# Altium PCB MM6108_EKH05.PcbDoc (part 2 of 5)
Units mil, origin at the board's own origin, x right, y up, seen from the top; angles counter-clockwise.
Board outline 6023.62 x 3425.2 mil, 4 copper layers (Top Layer, Ground Plane, Middle Layer, Bottom Layer), stack 76.15 mil thick; 212 components, 163 nets, 749 pads, 1477 vias.

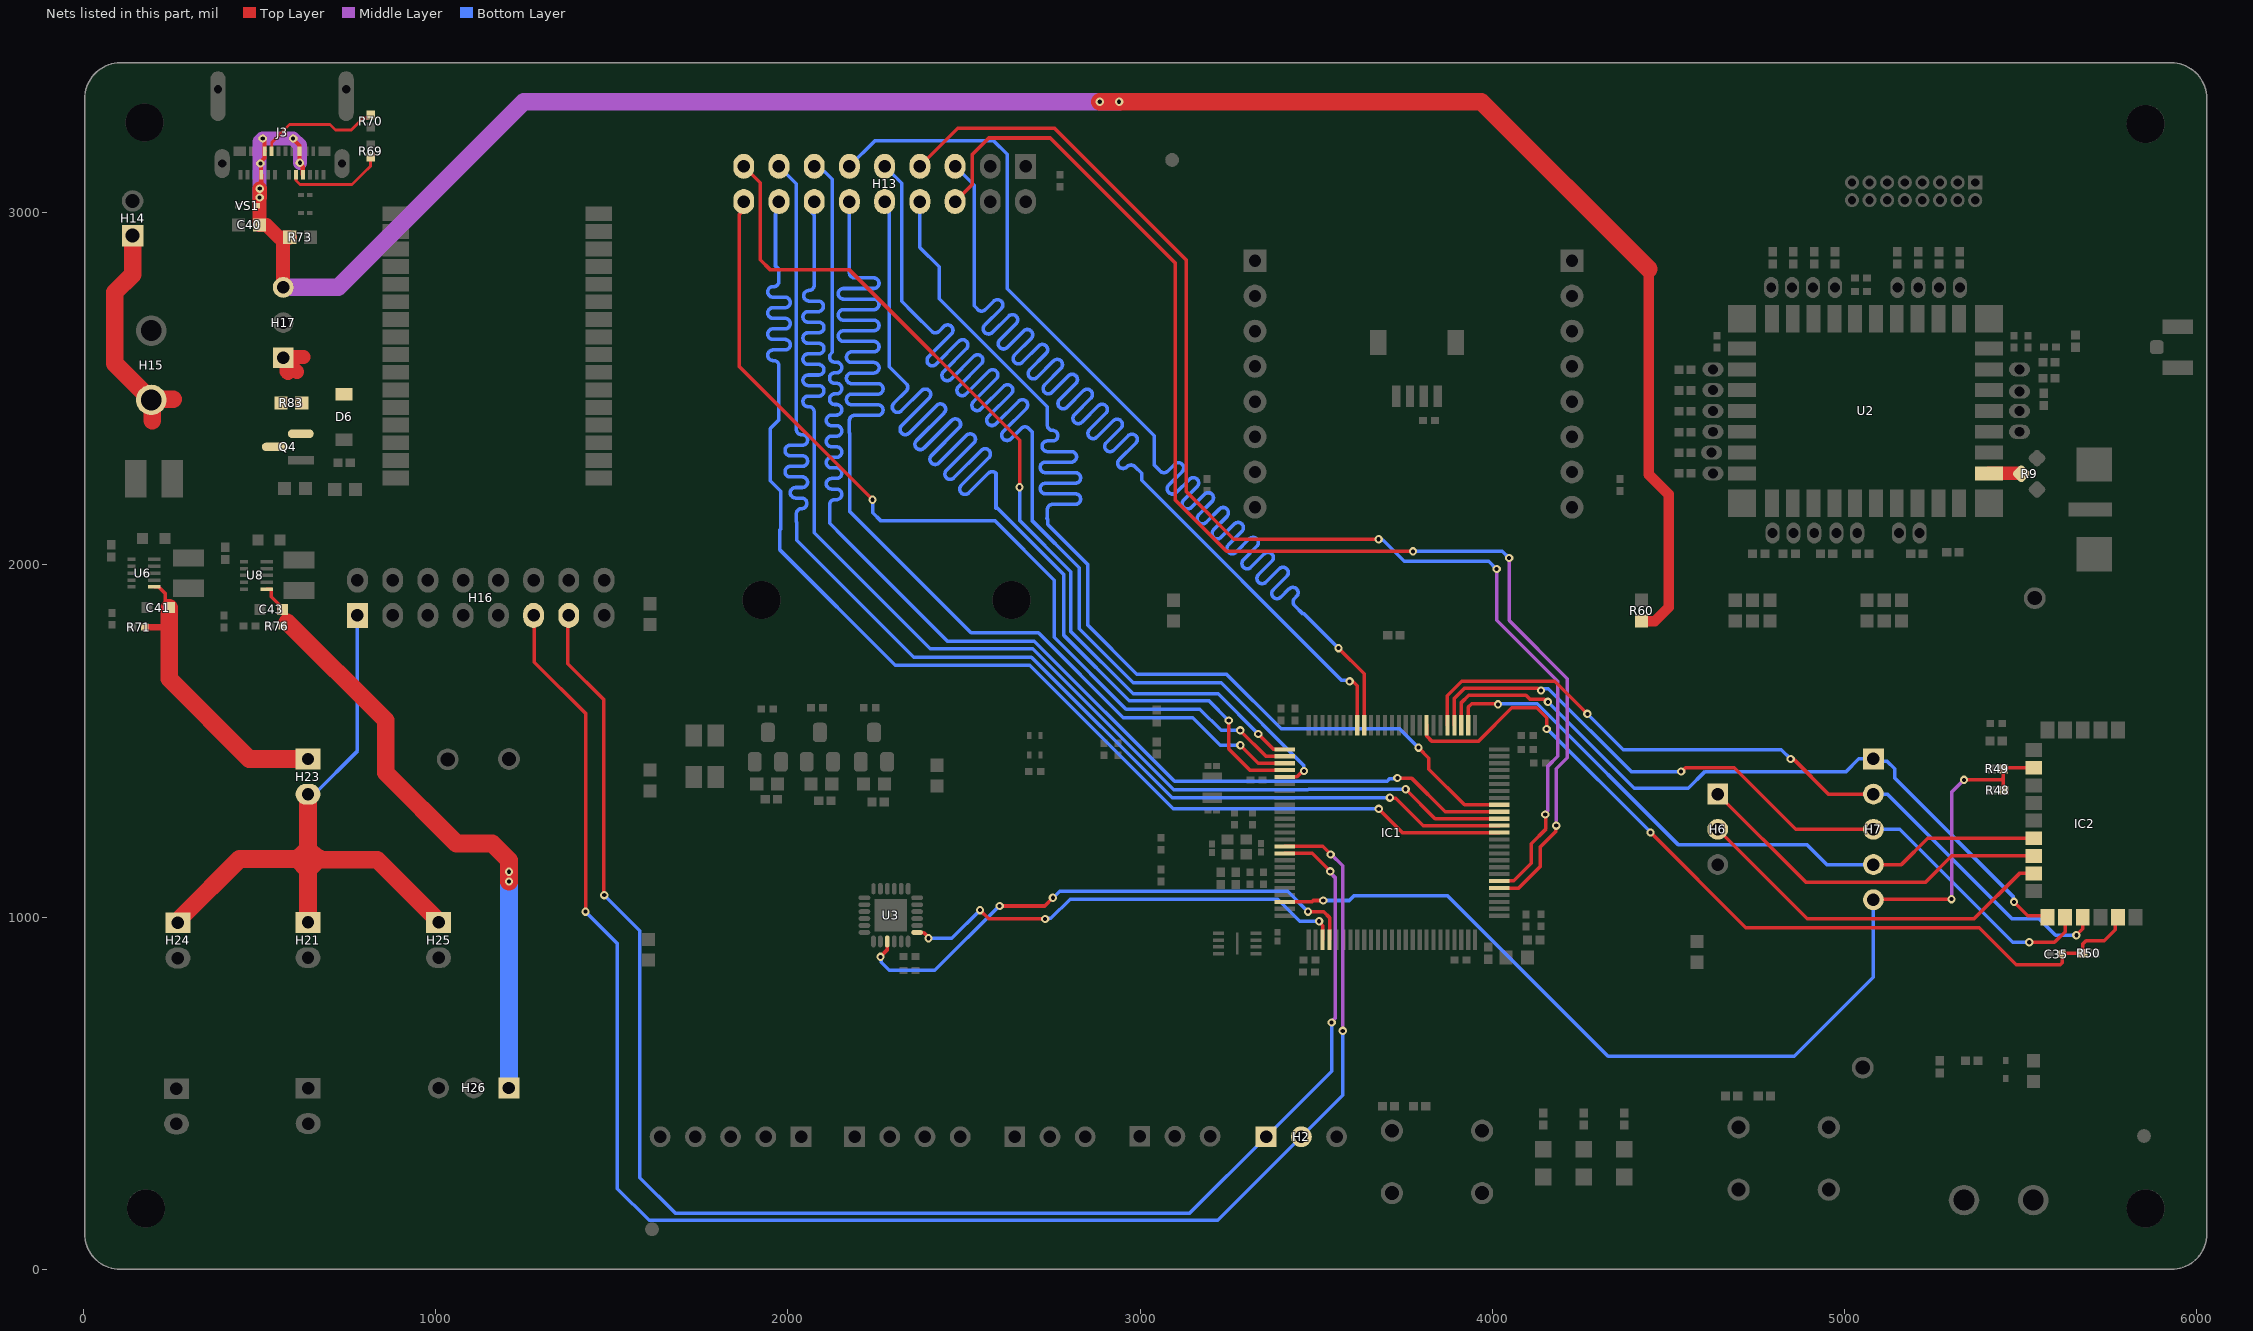
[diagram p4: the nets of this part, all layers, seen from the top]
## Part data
C1: library part CAP0157-11, "CAP CER 4.7UF 10V ±20% X5R 0402", Component Rating=X5R, Package=0402, Tolerance=20%, Voltage=10V
C2 C4 C6 C8 C11 C15 C16 C18 C28 C29 C31 C34 C37 C39 C45 C46 C47 C48: library part CAP0068-11, "CAP CER 100NF 50V ±10% X7R 0402", Component Rating=X7R, Package=0402, Tolerance=10%, Voltage=50V
C3 C5 C7 C9 C10 C14 C27 C30 C38: library part CAP0046-13, "CAP CER 10UF 10V 20% X5R 0402", Package=0402, Tolerance=20%, Voltage=10V
C12 C13 C32 C33: library part CAP0055-10, "CAP CER 2.2UF 25V ±20% X5R 0402", Component Rating=X5R, Package=0402, Tolerance=20%, Voltage=25V
C17 C21: library part CAP0168-10, "CAP CER 1UF 25V ±10% X5R 0402", Component Rating=X5R, Package=0402, Tolerance=10%, Voltage=25V
C19 C20: library part CAP0196-10, "CAP CER 100NF 10V ±10% X5R 0402", Component Rating=X5R, Package=0402, Tolerance=10%
C22 C23: library part CAP0010-6, "CAP CER 12PF 25V ±5% C0G/NP0 0201", Component Rating="C0G, NPO", Package=0201, Tolerance=5%, Voltage=25V
C24: library part CAP0134-6, "CAP CER 100NF 6.3V ±10% X5R 0201", Component Rating=X5R, Package=0201, Tolerance=10%
C25 C26: library part CAP0010-6, "CAP CER 12PF 25V ±5% C0G/NP0 0201", Component Rating="C0G, NPO", Package=0201, Tolerance=5%
C35: library part CAP0023-11, "CAP CER 10NF 25V ±10% X7R 0402", Component Rating=X7R, Package=0402, Tolerance=10%, Voltage=25V
C36: library part CAP0023-10, "CAP CER 10NF 25V ±10% X7R 0402", Component Rating=X7R, Package=0402, Tolerance=10%, Voltage=25V
C40: library part CAP0197-5, "CAP CER 10UF 25V ±20% X5R 0603", Component Rating=X5R, Package=0603, Tolerance=20%, Voltage=25V
C41 C43: library part CAP0243-1, "Multilayer Ceramic Capacitor, 22 uF, 6.3 V, ± 20%, X5R, 0603 [1608 Metric]", Case Code (Imperial)=0603, Case Code (Metric)=1608, Dielectric=X5R, Max Operating Temperature=85°C, Min Operating Temperature=-55°C, Package Quantity=1, Tolerance=20%, Voltage Rating=6.3V
C42 C44: library part CAP0244-1, "Multilayer Ceramic Capacitor, 10 uF, 6.3 V, ± 20%, X5R, 0603 [1608 Metric]", Case Code (Imperial)=0603, Case Code (Metric)=1608, Max Operating Temperature=85°C, Min Operating Temperature=-55°C, Package Quantity=1, Tolerance=20%, Voltage Rating=6.3V
C49: library part CAP0047-3, "CAP CER 100UF 10V ±20% X5R 1210", Component Rating=X5R, Package=1210, Tolerance=20%, Voltage=10V
D1: library part DIO0016-2, "LED, Red Clear,2.0V, SMD, 0805, RoHS", Component Rating="Clear, 2.0V", Package=SMD-0805
D2: library part DIO0015-2, "LED, Green Clear,2.0V, SMD, 0805, RoHS", Component Rating="Clear, 2.0V", Package=SMD-0805
D3: library part DIO0018-2, "LED, Blue Clear,3.3V, SMD, 0805, RoHS", Component Rating="Clear, 3.3V", Package=SMD-0805
D4: library part DIO0071-3, "TVS DIODE 3.3VWM 11.2VC SOD523", Package=SOD-123, Voltage=3.3V
D5: library part DIO0045-2, "LED, RGB, 624nm Red, 525nm Green, 470nm Blue LED Indication - Discrete 2V Red, 3.3V Green, 3.3V Blue 1206 (3216 Metric)", Component Rating="Clear, 3.3V", Current=20mA, Package="LED, 1206", Voltage=3.3V
D6: library part DIO0072-1, "DIODE ZENER 5.1V 500MW SOD-123"
D11 D12: library part DIO0043-4, "TVS DIODE 3VWM ST020", Package=0201, Power=20W, Voltage=3V
FID1 FID2 FID3: library part PAD0002-2, "1mm Round Fiducial, 0.5mm Space"
H1 H7: library part HDR0119-2, "2011 Series Single Row 5 Position 2.54 mm 3 A Straight Gold Flash Pin Header"
H2 H6 H8 H10 H17 H26: library part HDR0008-2, "Conn Straight Header 3x1 0.100\" 3 POS", Package=THRU-Hole
H4: library part JCK0091-1, "U.FL RF Connector", Package=SMT
H5: library part JCK0086-2, "CONN,Vertical FTSH Series,0.05\"16 Pins, Through Hole", Package="FTSH 108D"
H9: library part HDR0114-1, "Board Connector, 4 Contact(s), 1 Row(s), Male, Straight, Solder Terminal, 1x4"
H11 H15: library part JCK0020-1, "CONN TERM BLOCK 5MM 2POS", Package=THRU-Hole
H12: library part HDR0118-1, "QWIIC Connector, JST"
H13: library part HDR0112-1, "Board Connector, 18 Contact(s), 2 Row(s), Female, Straight, 0.1 inch Pitch, Solder Terminal, Locking"
H14: library part HDR0117-1, "Board Connector, 2 Contact(s), 1 Row(s), Male, Straight, Solder Terminal,"
H16: library part HDR0116-2
H19 H21 H22 H23 H24 H25: library part HDR0006-2, "Conn Straight Header 2x1 0.100\" 2 POS", Package=THRU-Hole
IC1: library part ICT0224-2, Package=LQFP-100
IC2: library part ICT0219-4, "BLUENRGM2SP"
J1 J2: library part HDR0120-3, "CONN RCPT 8POS 0.1 GOLD PCB"
J3: library part JCK0027-1, "CONN RCP USB3.1 TYPEC 24P SMD RA"
J5 J8 J9 J10 J11 J12 J13 J14 J15 J16 J17 J18 J19 J20 J21: library part CMP-00006-6, "Shunts/Jumper Connector", Manufacturer Series=QPC, Rated Current (Signal)=3A
J22: library part JCK0138-4, "Wanshih RF SMD SMA connector with 2 GND pillars - Smaller Connector Barrel"
L1: library part IND0038-5, "INDUCTOR 2.2UH 10% 0603 SMD", Current=300mA, DC Resistance=300mOhm, Frequency=80MHz, Package=0603, Tolerance=20%
L2: library part IND0062-6, "BEAD 60OHMS 2500MA 32 MOHM", Current=2.5A, DC Resistance=32mOhm, Package=0402
L3 L4: library part IND0139-3, Current=4, DC Resistance=27mOhm, Package=1008
M1 M2 M3 M4: library part PAD0031, "MH NPTH 3.00mm DIA 2.75mm HOLE"
MH1 MH2: library part PAD0009-2, "MH NPTH 3.00mm DIA 2.75mm HOLE"
Q1 Q2 Q3: library part TSR0015-4, "MOSFET N-CH 60V 190MA TO236AB", Current=190mA, Package=SOT-23-3, Power=265mW, Voltage=60V
Q4: library part TSR0020-1, "Small Signal Field-Effect Transistor", Avalanche Energy Rating (Eas)=33mJ, Drain Current-Max (Abs) (ID)=4.3A, Drain-source On Resistance-Max=50mR, DS Breakdown Voltage-Min=12V, Max Operating Temperature=150°C, Operating Mode="ENHANCEMENT MODE", Package Body Material=Plastic, Package Shape=Rectangular, Package Style="SMALL OUTLINEMeter", Peak Reflow Temperature (Cel)=260°C, Power Dissipation-Max (Abs)=1.3W, Pulsed Drain Current-Max (IDM)=34A, Time @ Peak Reflow Temperature-Max (s)=30s
R1 R2 R7 R8 R51: library part RES0043-8, "RES SMD 10K OHM ±1% 1/16W 0402", Package=0402, Power=1/16W, Tolerance=1%
R3 R4 R5 R6: library part RES0004-8, "RES SMD 1K OHM ±1% 1/10W 0402", Package=0402, Power=1/10W, Tolerance=1%
R9: library part RES0280, "Ohms Jumper Chip Resistor 0603 ( 1608 Metric) - RES_AC", Manufacturer 1=Rohm, Manufacturer 2=Yageo, Manufacturer Part Number 1=MCR03EZPJ000, Manufacturer Part Number 2=RC0603JR-070RL, Package=0603, Power=1/10W, Supplier Part Number 1=311-0.0GRCT-ND, Tolerance=5%
R10 R12 R31 R32 R33 R41 R42 R43 R47 R53 R54 R55 R56 R60 R61 R62 R63 R64 R73 R83: library part RES0119-6, "RES SMD 0R OHM ±5% 1/10W 0603", Package=0603, Power=1/10W, Tolerance=5%
R11 R14 R15 R16 R17 R18 R19 R20 R27 R28 R29 R30 R34 R37 R39 R40 R65 R66 R67: library part RES0002-8, "RES SMD 10K OHM ±1% 1/10W 0402", Package=0402, Power=1/10W, Tolerance=1%
R21 R22 R23 R24 R25 R26 R50: library part RES0086-8, "RES SMD 47K OHM ±1% 1/16W 0402", Package=0402, Power=1/16W, Tolerance=1%
R35: library part RES0023-9, "RES SMD 100K OHM ±1% 1/16W 0402", Package=0402, Power=1/16W, Tolerance=1%
R36: library part RES0252-6, "RES SMD 150K OHM 1% 1/10W 0402", Package=0402, Power=1/10W, Tolerance=1%
R46: library part RES0064-8, "RES SMD 220K OHM ±1% 1/16W 0402", Package=0402, Power=1/16W, Tolerance=1%
R48 R49: library part RES0244-8, "RES SMD 10K OHM ±0.1% 1/16W 0402", Package=0402, Power=1/16W, Tolerance=0.1%
R52: library part RES0104-6, "RES SMD 100R OHM ±0 .1% 1/16W 0603", Package=0603, Power=1/16W, Tolerance="0 .1%"
R57: library part RES0025-9, "RES SMD 330R OHM ±1% 1/16W 0402", Package=0402, Power=1/16W, Tolerance=1%
R58: library part RES0042-9, "RES SMD 1K OHM ±1% 1/16W 0402", Package=0402, Power=1/16W, Tolerance=1%
R59: library part RES0061-9, "RES SMD 220R OHM ±1% 1/16W 0402", Package=0402, Power=1/16W, Tolerance=1%
R68 R74: library part RES0044-8, "RES SMD 100K OHM ±1% 1/16W 0402", Package=0402, Power=1/16W, Tolerance=1%
R69 R70: library part RES0094-8, "RES SMD 5K1 OHM ±1% 1/16W 0402", Package=0402, Power=1/16W, Tolerance=1%
R71 R76: library part RES0254-2, "RES 511K OHM 1% 1/16W 0402", Manufacturer 1=YAGEO, Manufacturer Part Number 1=RC0402FR-07511KL, Package=0402, Power=1/16W, Tolerance=1%
R72 R77: library part RES0255-2, "RES 91K OHM 1% 1/16W 0402", Manufacturer 1=YAGEO, Manufacturer Part Number 1=RC0402FR-0791KL, Package=0402, Power=1/16W, Tolerance=1%
R75: library part RES0025-8, "RES SMD 330R OHM ±1% 1/16W 0402", Package=0402, Power=1/16W, Tolerance=1%
R82 R85: library part RES0002-9, "RES SMD 10K OHM ±1% 1/10W 0402", Package=0402, Power=1/10W, Tolerance=1%
R84: library part RES0057-9, "RES SMD 180K OHM ±1% 1/16W 0402", Package=0402, Power=1/16W, Tolerance=1%
S1 S2: library part SWH0038-1, "Keypad Switch, 1 Switches, SPST, Momentary-tactile, 0.05A, 24VDC, 2.06N, 4 PCB Hole Cnt, Solder Terminal, Through Hole-straight", Contact Current(DC)-Max=50mA, Contact DC Max Rating R Load=.05A@24VDC, Contact Voltage(DC)-Max=24V, Max Operating Temperature=85°C, Min Operating Temperature=-35°C, Operating Force-Max=2.06N
TP1 TP2 TP3 TP4: library part TPN0006-3, "Test Point PCB, Black 0.040\"D"
U1: library part ICT0220-1, Package=USON8
U2: library part MOD0010-3, "MM61xx-MF08"
U3: library part ICT0109-3, "IC, Accelerometers High-performance ultra-low-power 3-axis accelerometer digital output for industr", Component Rating=3-Axis, Package=QFN-24
U4: library part ICT0108-3, "IC, Humidity Temperature Sensor 0 ~ 100% RH I²C ±1.8% RH 6 s Surface Mount", Package=DFN-4
U5: library part MOD0006-3, "MIKROBUS Module"
U6 U8: library part ICT0222-5, Package=10-VFDFN
U7: library part MOD0018-3
VS1: library part DIO0073-1, "TVS Diode,5V@9.4Amp, SOD-523 SMD", Current=9.4A, Package=SOD-523, Voltage=5V
X1: library part OSC0002-3, "OSC XTAL 30MHZ 10PF 10PPM SMD2016", Component Rating=10pF, Package=2016, Tolerance=10ppm
X2: library part OSC0044-1, "Parallel - Fundamental Quartz Crystal, 0.032768MHz Nom", Frequency Stability=0.025%, Frequency Tolerance=20ppm, Load Capacitance=4pF, Max Operating Temperature=85°C, Min Operating Temperature=-40°C, Operating Frequency-Nom=0.032768

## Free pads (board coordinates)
  oval 60x40 hole 28: 31(4622.05,2318.9) 31(4625.98,2259.84) 31(4625.98,2377.95) 31(4625.98,2437.01) 31(4625.98,2496.06) 31(4625.98,2555.12) 31(5496.06,2377.95) 31(5496.06,2437.01) 31(5496.06,2492.13) 31(5496.06,2555.12)
  oval 40x60 hole 28: 31(4791.34,2787.4) 31(4795.28,2090.55) 31(4850.39,2787.4) 31(4854.33,2090.55) 31(4909.45,2787.4) 31(4913.39,2090.55) 31(4972.44,2787.4) 31(4976.38,2090.55) 31(5035.43,2090.55) 31(5149.61,2787.4) 31(5153.54,2090.55) 31(5208.66,2787.4) 31(5212.6,2090.55) 31(5267.72,2787.4) 31(5326.77,2787.4)

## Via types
v1: diameter 23.62, hole 11.81, Top Layer to Bottom Layer, tented both sides, 1477 vias

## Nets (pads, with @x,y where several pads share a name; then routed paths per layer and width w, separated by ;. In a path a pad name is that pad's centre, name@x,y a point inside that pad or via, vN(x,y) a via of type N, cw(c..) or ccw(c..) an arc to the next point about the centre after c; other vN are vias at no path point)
3V3: C41.2 H23.1 R71.1 U6.6 | length 843.4
  Top Layer w10: U6.6@201.34,1937.32 213.98,1937.32 232.71,1918.59 232.71,1889.48 C41.2@243.46,1878.74
  Top Layer w18: R71.1@173.77,1823.15 243.46,1823.15
  Top Layer w50: C41.2@243.46,1878.74 243.46,1823.15 243.46,1676.54 471,1449 H23.1@637.35,1449
3V3_SYS: H16.1 H21.1 H23.2 H24.1 H25.1 | length 1939
  Top Layer w10: 637.35,1237 655.13,1237
  Top Layer w50: H24.1@277.13,999.32 442.81,1165 592.83,1165 ; 603.92,1166.98 637.1,1133.8 670.28,1166.98 ; 609.54,1166.98 637.1,1194.54 664.66,1166.98 ; H21.1@637.35,985 637.35,1157.08 637.35,1194.54 637.35,1237 H23.2@637.35,1349 ; 662.56,1163 833.89,1163 997.57,999.32 997.57,989.53 1002.09,985 H25.1@1008,985
  Bottom Layer w10: H23.2@637.35,1349 655,1349 777.76,1471.76 H16.1@777.76,1856.69
4V3: C43.2 H26.1 R76.1 U8.6 | length 1751.7
  Top Layer w10: U8.6@520.43,1930.63 533.07,1930.63 533.15,1930.55 533.15,1909.97 C43.2@567.15,1875.97
  Top Layer w50: 578.92,1837.7 858,1558.62 858,1410 1059,1209 1160,1209 1208,1161 v1(1208,1101)
  Bottom Layer w50: H26.1@1208,515.12 v1(1208,1129)
+5V: C40.1 H17.3 J3.A4 J3.A9 J3.B4 J3.B9 R60.2 R73.2 VS1.K | length 6368.3
  Top Layer w12: v1(500.4,3068.15) 500.4,3071.29 504.72,3075.61 J3.A9@504.72,3107.48 504.24,3107.97 504.24,3137.67 v1(502.16,3139.75) 502.16,3142.9 514.08,3154.81 514.08,3173.92 J3.B4@514.57,3174.41 514.08,3174.9 514.08,3201.96 508.9,3207.14 v1(508.9,3210.28) ; v1(595.15,3210.4) 595.15,3208.83 612.99,3190.99 J3.B9@612.99,3174.41 ; v1@613.53,3142.37 J3.B9@613.53,3173.87 ; v1(614.17,3141.73) 614.17,3138.59 622.35,3130.41 622.35,3107.97 J3.A4@622.83,3107.48
  Top Layer w30: R60.2@4423.23,1840.55 4460.82,1840.55 4500,1879.73 4500,2200 4443.35,2256.65 4443.35,2840.11
  Top Layer w40: C40.1@499.53,2965 C40.1@500.15,2965 ; v1(500.4,3068.15) 500.4,3043.22 v1(500.15,3042.97) C40.1@500.15,2965 ; H17.3@566.93,2787.87 R73.2@566.93,2930 ; R73.2@585.47,2930 R73.2@566.93,2930 ; C40.1@500.15,2965 520,2965 555,2930 R73.2@566.93,2930
  Top Layer w50: v1(2885,3315) v1(2940,3315) 3968.46,3315 4443.35,2840.11
  Middle Layer w40: v1(500.15,3042.97) 500.15,3068 500,3068.15 500,3201.39 v1(508.9,3210.28) 509.02,3210.4 v1(595.15,3210.4) 614.17,3191.38 v1(614.17,3141.73)
  Middle Layer w50: H17.3@566.93,2787.87 722.87,2787.87 1250,3315 v1(2940,3315)
ACC_INT1: IC1.28 U3.7 | length 1299.2
  Top Layer w10: U3.7@2366.61,956.57 2367.33,955.85 2385.98,955.85 2399,942.83 v1(2399,940) ; v1(2545,1020) 2570,995 v1(2730,995) ; v1(3507.87,988.19) 3507.87,985.88 3517.72,976.04 IC1.28@3517.72,935.51
  Bottom Layer w10: v1(2399,940) 2465,940 v1(2545,1020) ; v1(2730,995) 2731.46,996.46 2746.46,996.46 2800.93,1050.93 3390.02,1050.93 3452.76,988.19 v1(3507.87,988.19)
ACC_INT2: IC1.29 U3.3 | length 1537.3
  Top Layer w10: v1(2262.7,887.22) 2262.7,888.05 2281.24,906.59 2281.24,930.26 U3.3@2281.96,930.98 ; v1(2600.75,1031.65) 2728.5,1031.65 v1(2751.97,1055.12) ; v1(3476.38,1015.75) 3520.52,1015.75 3537.4,998.87 IC1.29@3537.4,935.51
  Bottom Layer w10: v1(2262.7,887.22) 2264.89,885.02 2264.89,871.49 2287.38,849 2417,849 2599.65,1031.65 v1(2600.75,1031.65) ; v1(2751.97,1055.12) 2752.83,1055.12 2771.02,1073.31 3418.82,1073.31 v1(3476.38,1015.75)
ANT: R9.A U2.38 | length 92.5
  Top Layer w39: U2.38@5409.45,2259.84 5499.74,2259.84 5501.09,2258.49 R9.A@5501.35,2258.49
BAT_POS: H14.1 H15.2 Q4.3 R83.1 | length 652.9
  Top Layer w50: H14.1@139.45,2934.88 139.45,2824.45 88.93,2773.93 88.93,2571.86 H15.2@192.6,2468.19 ; 195,2410 195,2465.79 H15.2@192.6,2468.19 ; 255,2470 194.41,2470 H15.2@192.6,2468.19
BAT_VIN: D6.K H17.1 Q4.2 R83.2 | length 123.6
  Top Layer w40: 580,2545 576.46,2548.54 576.46,2578.35 H17.1@566.93,2587.87 569.05,2590 625,2590 ; H17.1@594.9,2559.9 606.46,2548.35
BLE_RESET_N: C35.2 IC1.83 IC2.19 R50.2 | length 2464.2
  Top Layer w10: IC1.83@3812.99,1544.8 3813.9,1543.9 3813.9,1513.09 3826.98,1500 3960.63,1500 4055.12,1594.49 4125.98,1594.49 4154.51,1565.97 4154.51,1534.67 v1(4153.79,1533.95) ; v1(4448.82,1240.16) 4718.98,970 5382.26,970 5487.26,865 5611.45,865 5617.3,870.86 5617.3,897.64 R50.2@5675.59,897.64 5676.38,897.64 5676.38,924.41 5685.04,933.07 5736.29,933.07 5767.72,964.49 5767.72,992.13 IC2.19@5775.59,1000
  Bottom Layer w10: v1(4153.79,1533.95) 4155.79,1533.95 4448.82,1240.92 v1(4448.82,1240.16)
BLE_SPI_CS: H7.4 IC1.77 IC2.11 | length 1882.4
  Top Layer w10: IC1.77@3931.1,1544.8 3931.1,1596.46 3940.69,1606.05 4013.87,1606.05 v1(4015.75,1604.17) ; H7.4@5081.42,1149.29 5161.1,1149.29 5235.83,1224.02 IC2.11@5536.22,1224.02
  Bottom Layer w10: v1(4015.75,1604.17) 4017.62,1606.05 4126.95,1606.05 4526.84,1206.16 4892.27,1206.16 4949.13,1149.29 H7.4@5081.42,1149.29
BLE_SPI_IRQ: H7.5 IC1.23 IC2.7 R48.2 R49.1 | length 3016.4
  Top Layer w10: IC1.23@3409.92,1043.31 3487.79,1043.31 3491.72,1047.24 v1(3519.6,1047.24) ; H7.5@5081.42,1049.29 5083.31,1051.18 v1(5303.15,1051.18) ; v1(5338.58,1389.76) 5444.76,1389.76 5450.39,1395.39 ; R48.2@5450.39,1362.2 5450.39,1395.39 ; IC2.7@5536.22,1424.02 5453.73,1424.02 R49.1@5450.39,1420.68 5450.39,1395.39
  Middle Layer w10: v1(5303.15,1051.18) 5303.15,1354.33 v1(5338.58,1389.76)
  Bottom Layer w10: v1(3519.6,1047.24) 3593.72,1047.24 3607.86,1061.38 3871.69,1061.38 4328.07,605 4856.97,605 5081.42,829.45 H7.5@5081.42,1049.29
BLE_SPI_MISO: H7.3 IC1.79 IC2.16 | length 2186.9
  Top Layer w10: IC1.79@3891.73,1544.8 3891.73,1620.78 3920.56,1649.61 4128.05,1649.61 4134.11,1643.54 v1(4137.8,1643.54) ; v1(4535.43,1413.39) 4537.49,1413.39 4548.1,1424 4686.24,1424 4860.94,1249.29 H7.3@5081.42,1249.29 ; v1(5524.02,928.55) 5595.33,928.55 5625.59,958.82 IC2.16@5625.59,1000
  Bottom Layer w10: v1(4137.8,1643.54) 4141.48,1643.54 4146.28,1648.34 4158.75,1648.34 4393.7,1413.39 v1(4535.43,1413.39) ; H7.3@5081.42,1249.29 5156.19,1249.29 5476.93,928.55 v1(5524.02,928.55)
BLE_SPI_MOSI: H7.2 IC1.80 IC2.17 | length 2243.2
  Top Layer w10: IC1.80@3872.05,1544.8 3872.05,1628.55 3912.78,1669.29 4177.17,1669.29 v1(4269.32,1577.14) ; v1(4846.46,1448.82) 4849.06,1446.21 4856.69,1446.21 4856.95,1445.94 4857.2,1445.94 4953.86,1349.29 H7.2@5081.42,1349.29 ; v1(5657.48,948.82) 5675.59,966.93 IC2.17@5675.59,1000
  Bottom Layer w10: v1(4269.32,1577.14) 4371.46,1475 4820.28,1475 v1(4846.46,1448.82) ; H7.2@5081.42,1349.29 5082.29,1348.42 5121.58,1348.42 5473.94,996.06 5551.18,996.06 5598.43,948.82 v1(5657.48,948.82)
BLE_SPI_SCK: H7.1 IC1.78 IC2.15 | length 2089.9
  Top Layer w10: IC1.78@3911.42,1544.8 3911.87,1545.26 3911.87,1609.38 3932.41,1629.92 4095.08,1629.92 4105.87,1619.13 4145.66,1619.13 4153.58,1611.21 v1(4157.27,1611.21) ; v1(5480.31,1043.31) 5519.69,1003.94 5571.65,1003.94 IC2.15@5575.59,1000
  Bottom Layer w10: v1(4157.27,1611.21) 4402.34,1366.14 4556.14,1366.14 4603.39,1413.39 5003.94,1413.39 5039.84,1449.29 H7.1@5081.42,1449.29 5087.8,1442.91 5120.09,1442.91 5141.73,1421.26 5141.73,1394.94 5477.88,1058.79 5477.88,1045.74 v1(5480.31,1043.31)
BLE_SWCLK: H6.1 IC2.12 | length 1032.1
  Top Layer w10: H6.1@4639.37,1349.29 4890.24,1098.43 5228.35,1098.43 5303.94,1174.02 IC2.12@5536.22,1174.02
BLE_SWDIO: H6.2 IC2.13 | length 1055.6
  Top Layer w10: H6.2@4639.37,1249.29 4893.66,995 5367.05,995 5496.06,1124.02 IC2.13@5536.22,1124.02
CAM_PWDN: H13.18 IC1.2 | length 2596.5
  Top Layer w10: H13.18@1874.41,3031.5 1865.02,3022.11 1865.02,2998.02 1862.2,2995.2 1862.2,2562.99 v1(2240.16,2185.04) ; v1(3284.13,1530.33) 3284.13,1529.59 3357.03,1456.69 IC1.2@3409.92,1456.69
  Bottom Layer w10: v1(2240.16,2185.04) 2240.16,2148.42 2262.59,2125.98 2586.61,2125.98 2755.91,1956.69 2755.91,1794.31 2959.67,1590.55 3169.45,1590.55 3229.67,1530.33 v1(3284.13,1530.33)
CAM_RESET: H13.17 IC1.1 | length 2582.2
  Top Layer w10: H13.17@1874.41,3131.5 1921.26,3084.65 1921.26,2866.14 1948.82,2838.58 2173.23,2838.58 2657.48,2354.33 v1(2657.48,2220.47) ; v1(3335,1520) 3377.72,1477.28 3409.02,1477.28 IC1.1@3409.92,1476.38
  Bottom Layer w10: v1(2657.48,2220.47) 2657.48,2125.98 2803.15,1980.31 2803.15,1810.74 2980.03,1633.86 3221.14,1633.86 v1(3335,1520)
CAM_XCLK: H13.8 IC1.67 | length 3411.7
  Top Layer w10: v1(3789.8,1481.21) 3819.45,1451.57 3819.45,1420.07 3920.62,1318.9 IC1.67@4019.21,1318.9
  Bottom Layer w10: H13.8@2374.41,3031.5 2374.41,2901.18 2429.13,2846.46 2429.13,2755.91 2736.22,2448.82 2736.22,2429.13 2736.22,2396.87 ccw(c2751.22,2396.87) 2751.22,2381.87 cw(c2751.22,2366.87) 2751.22,2351.87 2736.22,2351.87 ccw(c2736.22,2336.87) 2736.22,2321.87 2804.16,2321.87 cw(c2804.16,2306.87) 2804.16,2291.87 2730.79,2291.87 ccw(c2730.79,2276.87) 2730.79,2261.87 2815.61,2261.87 cw(c2815.61,2246.87) 2815.61,2231.87 2730.79,2231.87 ccw(c2730.79,2216.87) 2730.79,2201.87 2815.61,2201.87 cw(c2815.61,2186.87) 2815.61,2171.87 2751.22,2171.87 ccw(c2751.22,2156.87) 2736.22,2156.87 2736.22,2133.86 2734.25,2131.89 2737.16,2128.99 2737.16,2123.16 2737.16,2114.77 2850.39,2001.53 2850.39,1829.61 2990,1690 3245,1690 3400,1535 3736.02,1535 v1(3789.8,1481.21)
CC1: J3.A5 R69.1 | length 279.7
  Top Layer w8: J3.A5@603.15,3107.48 603.54,3107.09 603.54,3091.46 615,3080 762.32,3080 806.01,3123.69 806.8,3123.69 815,3131.89 R69.1@815,3157.68
CC2: J3.B5 R70.1 | length 350.8
  Top Layer w8: J3.B5@534.25,3174.41 534.25,3199.25 585,3250 700,3250 715,3235 760,3235 793.33,3268.33 806.8,3268.33 815,3276.54 R70.1@815,3277.32
DBG_UART_STM_RX: H2.2 H16.11 IC1.15 | length 4807.8
  Top Layer w10: H16.11@1280,1855.9 1280,1723.94 1425.2,1578.74 v1(1425.2,1015.75) ; IC1.15@3409.92,1200.79 3518.59,1200.79 3540.42,1178.95 v1(3540.42,1177.64)
  Middle Layer w10: v1(3540.42,1177.64) 3542.84,1177.64 3574.8,1145.67 v1(3574.8,677.17)
  Bottom Layer w10: v1(1425.2,1015.75) 1515.75,925.2 1515.75,229.25 1605.94,139.06 3219.74,139.06 H2.2@3457.38,376.69 3574.8,494.11 v1(3574.8,677.17)
DBG_UART_STM_TX: H2.1 H16.13 IC1.16 | length 4578.9
  Top Layer w10: H16.13@1375,1854.84 1375,1719.49 1476.38,1618.11 1476.38,1064.66 v1(1478.44,1062.6) ; IC1.16@3409.92,1181.1 3488.19,1181.1 v1(3539.37,1129.92)
  Middle Layer w10: v1(3539.37,1129.92) 3539.37,1126.24 3553.03,1112.57 3553.03,713.46 3543.31,703.73 v1(3543.31,700.79)
  Bottom Layer w10: v1(1478.44,1062.6) 1579.37,961.67 1579.37,260.63 1680,160 3140.69,160 H2.1@3357.38,376.69 3543.31,562.62 v1(3543.31,700.79)
DCMI_D0: H13.16 IC1.63 | length 3739.8
  Top Layer w10: v1(3677.22,1307.43) 3677.22,1307.04 3744.09,1240.16 IC1.63@4019.21,1240.16
  Bottom Layer w10: H13.16@1974.41,3031.5 1965.02,3022.11 1965.02,2995.66 1964.57,2995.2 1964.57,2848.43 1974.41,2838.58 1974.41,2805.12 cw(c1959.41,2805.12) 1959.41,2790.12 1957.41,2790.12 ccw(c1957.41,2775.12) 1957.41,2760.12 1991.41,2760.12 cw(c1991.41,2745.12) 1991.41,2730.12 1957.41,2730.12 ccw(c1957.41,2715.12) 1957.41,2700.12 1991.41,2700.12 cw(c1991.41,2685.12) 1991.41,2670.12 1957.41,2670.12 ccw(c1957.41,2655.12) 1957.41,2640.12 1991.41,2640.12 cw(c1991.41,2625.12) 1991.41,2610.12 1957.41,2610.12 ccw(c1957.41,2595.12) 1957.41,2580.12 1959.41,2580.12 cw(c1959.41,2565.12) 1974.41,2565.12 1974.41,2560.12 1974.41,2411.72 1949.83,2387.14 1949.83,2238.73 1979.05,2209.52 1979.05,2101.24 1977.19,2099.39 1977.19,2042.5 2304.95,1714.73 2686.84,1714.73 3094.15,1307.43 v1(3677.22,1307.43)
DCMI_D1: H13.15 IC1.64 | length 3724.6
  Top Layer w10: v1(3708.66,1339.39) 3710.15,1337.9 3725.09,1337.9 3803.15,1259.84 IC1.64@4019.21,1259.84
  Bottom Layer w10: H13.15@1974.16,3131.74 2023.62,3082.28 2023.62,2389.76 2023.62,2384.76 ccw(c2038.62,2384.76) 2038.62,2369.76 2040.62,2369.76 cw(c2040.62,2354.76) 2040.62,2339.76 2006.62,2339.76 ccw(c2006.62,2324.76) 2006.62,2309.76 2040.62,2309.76 cw(c2040.62,2294.76) 2040.62,2279.76 2006.62,2279.76 ccw(c2006.62,2264.76) 2006.62,2249.76 2040.62,2249.76 cw(c2040.62,2234.76) 2040.62,2219.76 2021.59,2219.76 ccw(c2021.59,2204.76) 2021.59,2189.76 2038.62,2189.76 cw(c2038.62,2174.76) 2038.62,2159.76 ccw(c2038.62,2144.76) 2023.62,2144.76 2023.62,2122.05 2024.67,2121 2024.67,2069.82 2356.51,1737.97 2691.16,1737.97 3090.55,1338.58 3707.85,1338.58 v1(3708.66,1339.39)
DCMI_D2: H13.14 IC1.65 | length 3734.4
  Top Layer w10: v1(3753.42,1362.96) 3836.85,1279.53 IC1.65@4019.21,1279.53
  Bottom Layer w10: H13.14@2074.41,3031.5 2060.1,3017.18 2060.1,3006.49 2074.41,2992.17 2074.41,2826.77 2074.41,2794.13 cw(c2059.41,2794.13) 2059.41,2779.13 ccw(c2059.41,2764.13) 2059.41,2749.13 2085.65,2749.13 cw(c2085.65,2734.13) 2085.65,2719.13 2057.41,2719.13 ccw(c2057.41,2704.13) 2057.41,2689.13 2087.11,2689.13 cw(c2087.11,2674.13) 2087.11,2659.13 2057.41,2659.13 ccw(c2057.41,2644.13) 2057.41,2629.13 2087.11,2629.13 cw(c2087.11,2614.13) 2087.11,2599.13 2057.41,2599.13 ccw(c2057.41,2584.13) 2057.41,2569.13 2087.11,2569.13 cw(c2087.11,2554.13) 2087.11,2539.13 2057.41,2539.13 ccw(c2057.41,2524.13) 2057.41,2509.13 2087.11,2509.13 cw(c2087.11,2494.13) 2087.11,2479.13 2057.41,2479.13 ccw(c2057.41,2464.13) 2057.41,2449.13 2059.41,2449.13 cw(c2059.41,2434.13) 2074.41,2434.13 2074.41,2429.13 2074.41,2090.94 2403.52,1761.83 2694.86,1761.83 3095.5,1361.19 3476.08,1361.19 3477.85,1362.96 v1(3753.42,1362.96)
DCMI_D3: H13.13 IC1.66 | length 3675
  Top Layer w10: v1(3730,1395) 3770,1395 3865.79,1299.21 IC1.66@4019.21,1299.21
  Bottom Layer w10: H13.13@2074.41,3131.5 2089.7,3116.2 2104.27,3116.2 2125.98,3094.49 2125.98,2603.26 2118.11,2595.39 2118.11,2590.39 ccw(c2133.11,2590.39) 2133.11,2575.39 2137.8,2575.39 cw(c2137.8,2560.39) 2137.8,2545.39 2132.91,2545.39 ccw(c2132.91,2530.39) 2132.91,2515.39 2137.8,2515.39 cw(c2137.8,2500.39) 2137.8,2485.39 2132.91,2485.39 ccw(c2132.91,2470.39) 2132.91,2455.39 2137.8,2455.39 cw(c2137.8,2440.39) 2137.8,2425.39 2123.81,2425.39 ccw(c2123.81,2410.39) 2123.81,2395.39 2137.8,2395.39 cw(c2137.8,2380.39) 2137.8,2365.39 2123.81,2365.39 ccw(c2123.81,2350.39) 2123.81,2335.39 2137.8,2335.39 cw(c2137.8,2320.39) 2137.8,2305.39 2123.81,2305.39 ccw(c2123.81,2290.39) 2123.81,2275.39 2137.8,2275.39 cw(c2137.8,2260.39) 2137.8,2245.39 2123.81,2245.39 ccw(c2123.81,2230.39) 2123.81,2215.39 2137.8,2215.39 cw(c2137.8,2200.39) 2137.8,2185.39 2133.11,2185.39 ccw(c2133.11,2170.39) 2118.11,2170.39 2118.11,2118.11 2157.06,2079.16 2452.69,1783.53 2699.6,1783.53 3097.3,1385.83 3700.9,1385.83 3707.46,1392.39 3727.39,1392.39 v1(3730,1395)
DCMI_D4: H13.12 IC1.3 | length 3697.7
  Top Layer w10: v1(3284.24,1488.2) 3335.43,1437.01 IC1.3@3409.92,1437.01
  Bottom Layer w10: H13.12@2174.41,3031.5 2174.41,2862.2 2174.41,2829.69 ccw(c2189.41,2829.69) 2189.41,2814.69 2243.41,2814.69 cw(c2243.41,2799.69) 2243.41,2784.69 2157.41,2784.69 ccw(c2157.41,2769.69) 2157.41,2754.69 2243.41,2754.69 cw(c2243.41,2739.69) 2243.41,2724.69 2157.41,2724.69 ccw(c2157.41,2709.69) 2157.41,2694.69 2243.41,2694.69 cw(c2243.41,2679.69) 2243.41,2664.69 2157.41,2664.69 ccw(c2157.41,2649.69) 2157.41,2634.69 2243.41,2634.69 cw(c2243.41,2619.69) 2243.41,2604.69 2180.79,2604.69 ccw(c2180.79,2589.69) 2180.79,2574.69 2243.46,2574.69 cw(c2243.46,2559.69) 2243.46,2544.69 2180.68,2544.69 ccw(c2180.68,2529.69) 2180.68,2514.69 2255.09,2514.69 cw(c2255.09,2499.69) 2255.09,2484.69 2180.68,2484.69 ccw(c2180.68,2469.69) 2180.68,2454.69 2255.09,2454.69 cw(c2255.09,2439.69) 2255.09,2424.69 2189.41,2424.69 ccw(c2189.41,2409.69) 2174.41,2409.69 2174.41,2374.69 2175.19,2373.91 2175.19,2151.58 2519.69,1807.09 2711.08,1807.09 2952.25,1565.92 3149.08,1565.92 3226.8,1488.2 v1(3284.24,1488.2)
DCMI_D5: H13.11 IC1.92 | length 3718.9
  Top Layer w10: v1(3562.99,1763.78) 3635.83,1690.94 IC1.92@3635.83,1544.8
  Bottom Layer w10: H13.11@2174.41,3131.5 2247.64,3204.72 2582.68,3204.72 2622.05,3165.35 2622.05,2783.46 3039.37,2366.14 3039.37,2283.46 3053.15,2269.68 3056.69,2266.15 ccw(c3067.29,2276.76) 3077.9,2266.15 3097.64,2285.9 cw(c3108.25,2275.29) 3118.86,2285.9 cw(c3108.25,2275.29) 3118.86,2264.68 3080.9,2226.72 ccw(c3091.5,2216.12) 3080.9,2205.51 ccw(c3091.5,2216.12) 3102.11,2205.51 3140.07,2243.47 cw(c3150.68,2232.86) 3161.28,2243.47 cw(c3150.68,2232.86) 3161.28,2222.26 3123.32,2184.3 ccw(c3133.93,2173.69) 3123.32,2163.08 ccw(c3133.93,2173.69) 3144.54,2163.08 3182.5,2201.04 cw(c3193.1,2190.44) 3203.71,2201.04 cw(c3193.1,2190.44) 3203.71,2179.83 3165.75,2141.87 ccw(c3176.36,2131.26) 3165.75,2120.66 ccw(c3176.36,2131.26) 3186.96,2120.66 3224.92,2158.62 cw(c3235.53,2148.01) 3246.14,2158.62 cw(c3235.53,2148.01) 3246.14,2137.4 3208.18,2099.44 ccw(c3218.78,2088.84) 3208.18,2078.23 ccw(c3218.78,2088.84) 3229.39,2078.23 3267.35,2116.19 cw(c3277.96,2105.58) 3288.56,2116.19 cw(c3277.96,2105.58) 3288.56,2094.98 3250.6,2057.02 ccw(c3261.21,2046.41) 3250.6,2035.8 ccw(c3261.21,2046.41) 3271.82,2035.8 3309.78,2073.76 cw(c3320.38,2063.16) 3330.99,2073.76 cw(c3320.38,2063.16) 3330.99,2052.55 3293.03,2014.59 ccw(c3303.64,2003.98) 3293.03,1993.38 ccw(c3303.64,2003.98) 3314.24,1993.38 3352.2,2031.34 cw(c3362.81,2020.73) 3373.42,2031.34 cw(c3362.81,2020.73) 3373.42,2010.12 3335.46,1972.16 ccw(c3346.06,1961.56) 3335.46,1950.95 ccw(c3346.06,1961.56) 3356.67,1950.95 3394.63,1988.91 cw(c3405.24,1978.3) 3415.84,1988.91 cw(c3405.24,1978.3) 3415.84,1967.7 3377.88,1929.74 ccw(c3388.49,1919.13) 3377.88,1908.52 ccw(c3388.49,1919.13) 3399.1,1908.52 3422.49,1931.92 cw(c3433.1,1921.31) 3443.7,1931.92 cw(c3433.1,1921.31) 3443.7,1910.7 3438.52,1905.52 ccw(c3449.13,1894.92) 3438.52,1884.31 3462.11,1860.73 3466.05,1860.73 v1(3562.99,1763.78)
DCMI_D6: H13.10 IC1.4 | length 3688.9
  Top Layer w10: v1(3251.33,1558.08) 3251.33,1477.41 3311.41,1417.32 IC1.4@3409.92,1417.32
  Bottom Layer w10: H13.10@2274.41,3031.5 2274.41,3012.32 2287.4,2999.32 2287.4,2562.99 2335.63,2514.76 cw(c2325.02,2504.16) 2335.63,2493.55 2300.58,2458.5 ccw(c2311.19,2447.9) 2300.58,2437.29 ccw(c2311.19,2447.9) 2321.8,2437.29 2379.47,2494.96 cw(c2390.08,2484.36) 2400.68,2494.96 cw(c2390.08,2484.36) 2400.68,2473.75 2322.39,2395.46 ccw(c2333,2384.85) 2322.39,2374.25 ccw(c2333,2384.85) 2343.61,2374.25 2421.9,2452.54 cw(c2432.5,2441.93) 2443.11,2452.54 cw(c2432.5,2441.93) 2443.11,2431.33 2364.82,2353.03 ccw(c2375.43,2342.43) 2364.82,2331.82 ccw(c2375.43,2342.43) 2386.03,2331.82 2464.32,2410.11 cw(c2474.93,2399.51) 2485.54,2410.11 cw(c2474.93,2399.51) 2485.54,2388.9 2407.25,2310.61 ccw(c2417.85,2300) 2407.25,2289.39 ccw(c2417.85,2300) 2428.46,2289.39 2506.75,2367.69 cw(c2517.36,2357.08) 2527.96,2367.69 cw(c2517.36,2357.08) 2527.96,2346.47 2449.67,2268.18 ccw(c2460.28,2257.57) 2449.67,2246.97 ccw(c2460.28,2257.57) 2470.89,2246.97 2549.18,2325.26 cw(c2559.78,2314.65) 2570.39,2325.26 cw(c2559.78,2314.65) 2570.39,2304.05 2492.1,2225.75 ccw(c2502.7,2215.15) 2492.1,2204.54 ccw(c2502.7,2215.15) 2513.31,2204.54 2568.98,2260.21 cw(c2579.58,2249.6) 2590.19,2260.21 2590.55,2259.84 2590.55,2232.28 2590.55,2161.42 2594.49,2161.42 2783.46,1972.44 2783.46,1799.66 2968.95,1614.17 3195.23,1614.17 v1(3251.33,1558.08)
DCMI_D7: H13.9 IC1.5 | length 3713.6
  Top Layer w10: IC1.5@3409.92,1397.64 3410.83,1398.54 3444.86,1398.54 3461.31,1415 v1(3465,1415)
  Bottom Layer w10: H13.9@2274.41,3131.5 2322.83,3083.07 2322.83,2748.03 2356.3,2714.57 2407.7,2663.17 ccw(c2418.31,2673.77) 2428.91,2663.17 2442.84,2677.09 cw(c2453.45,2666.48) 2464.05,2677.09 cw(c2453.44,2666.48) 2464.05,2655.88 2399.06,2590.89 ccw(c2409.67,2580.28) 2399.06,2569.68 ccw(c2409.67,2580.28) 2420.28,2569.68 2485.26,2634.66 cw(c2495.87,2624.06) 2506.48,2634.66 cw(c2495.87,2624.06) 2506.48,2613.45 2441.49,2548.46 ccw(c2452.1,2537.86) 2441.49,2527.25 ccw(c2452.1,2537.86) 2462.7,2527.25 2527.69,2592.24 cw(c2538.3,2581.63) 2548.9,2592.24 cw(c2538.3,2581.63) 2548.9,2571.02 2483.92,2506.04 ccw(c2494.52,2495.43) 2483.92,2484.82 ccw(c2494.52,2495.43) 2505.13,2484.82 2570.12,2549.81 cw(c2580.72,2539.2) 2591.33,2549.81 cw(c2580.72,2539.2) 2591.33,2528.6 2526.34,2463.61 ccw(c2536.95,2453) 2526.34,2442.4 ccw(c2536.95,2453) 2547.56,2442.4 2612.54,2507.38 cw(c2623.15,2496.78) 2633.76,2507.38 cw(c2623.15,2496.78) 2633.76,2486.17 2568.77,2421.18 ccw(c2579.38,2410.58) 2568.77,2399.97 ccw(c2579.38,2410.58) 2589.98,2399.97 2654.97,2464.96 cw(c2665.58,2454.35) 2676.18,2464.96 cw(c2665.58,2454.35) 2676.18,2443.75 2611.2,2378.76 ccw(c2621.8,2368.15) 2611.2,2357.54 ccw(c2621.8,2368.15) 2632.41,2357.54 2662.26,2387.39 cw(c2672.87,2376.79) 2683.47,2387.39 2687.01,2383.86 2692.91,2377.95 2692.91,2125.98 2826.77,1992.13 2826.77,1818.74 2980.51,1665 3230,1665 3463.54,1431.46 3463.54,1416.46 v1(3465,1415)
DCMI_HSYNC: H13.6 IC1.55 | length 3703.5
  Top Layer w10: H13.6@2474.41,3031.5 2523.62,3080.71 2523.62,3165.35 2570.19,3211.92 2744.77,3211.92 3100,2856.69 3100,2183.46 3245.01,2038.45 v1(3774.48,2038.45) ; IC1.55@4019.21,1082.68 4074.8,1082.68 4135,1142.87 4135,1197.99 4180.02,1243.01 4180.02,1258.76 v1(4181.1,1259.84)
  Middle Layer w10: v1(4047.24,2019.68) 4047.24,1842.35 4212.6,1677 4212.6,1452.76 4181.1,1421.26 v1(4181.1,1259.84)
  Bottom Layer w10: v1(3774.48,2038.45) 4028.1,2038.45 4046.86,2019.68 v1(4047.24,2019.68)
DCMI_PIXCLK: H13.7 IC1.56 | length 3637.1
  Top Layer w10: H13.7@2374.41,3131.5 2482.39,3239.48 2756.58,3239.48 3130,2866.06 3130,2208.58 3265.65,2072.93 v1(3676.77,2072.93) ; IC1.56@4019.21,1102.36 4020.12,1103.27 4059.96,1103.27 4110,1153.31 4110,1208.43 4151.87,1250.29 4151.87,1289.08 v1(4149.61,1291.34)
  Middle Layer w10: v1(4011.81,1988.19) 4011.81,1842.52 4185.04,1669.29 4185.04,1456.69 4157.48,1429.13 4157.48,1302.9 4149.61,1295.02 v1(4149.61,1291.34)
  Bottom Layer w10: v1(3676.77,2072.93) 3679.38,2070.32 3689.52,2070.32 3749.84,2010 3989.37,2010 4011.19,1988.19 v1(4011.81,1988.19)
DCMI_VSYNC: H13.5 IC1.93 | length 3709
  Top Layer w10: v1(3594.49,1669.29) 3597.09,1666.68 3606.08,1666.68 3616.14,1656.62 IC1.93@3616.14,1544.8
  Bottom Layer w10: H13.5@2474.41,3131.5 2528.41,3077.49 2528.41,2735.37 2535.43,2728.35 2538.97,2724.81 ccw(c2549.58,2735.42) 2560.18,2724.81 2584.15,2748.78 cw(c2594.76,2738.17) 2605.36,2748.78 cw(c2594.76,2738.17) 2605.36,2727.56 2558.77,2680.97 ccw(c2569.37,2670.36) 2558.77,2659.76 ccw(c2569.37,2670.36) 2579.98,2659.76 2626.58,2706.35 cw(c2637.18,2695.74) 2647.79,2706.35 cw(c2637.18,2695.74) 2647.79,2685.14 2601.19,2638.54 ccw(c2611.8,2627.94) 2601.19,2617.33 ccw(c2611.8,2627.94) 2622.41,2617.33 2669,2663.93 cw(c2679.61,2653.32) 2690.22,2663.93 cw(c2679.61,2653.32) 2690.22,2642.71 2643.62,2596.12 ccw(c2654.23,2585.51) 2643.62,2574.9 ccw(c2654.23,2585.51) 2664.83,2574.9 2711.43,2621.5 cw(c2722.04,2610.89) 2732.64,2621.5 cw(c2722.04,2610.89) 2732.64,2600.29 2686.05,2553.69 ccw(c2696.65,2543.08) 2686.05,2532.48 ccw(c2696.65,2543.08) 2707.26,2532.48 2753.85,2579.07 cw(c2764.46,2568.47) 2775.07,2579.07 cw(c2764.46,2568.47) 2775.07,2557.86 2728.47,2511.26 ccw(c2739.08,2500.66) 2728.47,2490.05 ccw(c2739.08,2500.66) 2749.69,2490.05 2796.28,2536.65 cw(c2806.89,2526.04) 2817.49,2536.65 cw(c2806.89,2526.04) 2817.49,2515.43 2770.9,2468.84 ccw(c2781.51,2458.23) 2770.9,2447.62 ccw(c2781.51,2458.23) 2792.11,2447.62 2838.71,2494.22 cw(c2849.31,2483.61) 2859.92,2494.22 cw(c2849.31,2483.61) 2859.92,2473.01 2813.33,2426.41 ccw(c2823.93,2415.8) 2813.33,2405.2 ccw(c2823.93,2415.8) 2834.54,2405.2 2881.13,2451.79 cw(c2891.74,2441.19) 2902.35,2451.79 cw(c2891.74,2441.19) 2902.35,2430.58 2855.75,2383.98 ccw(c2866.36,2373.38) 2855.75,2362.77 ccw(c2866.36,2373.38) 2876.97,2362.77 2923.56,2409.37 cw(c2934.17,2398.76) 2944.77,2409.37 cw(c2934.17,2398.76) 2944.77,2388.15 2903.47,2346.85 ccw(c2914.08,2336.24) 2903.47,2325.64 ccw(c2914.08,2336.24) 2924.69,2325.64 2965.99,2366.94 cw(c2976.59,2356.33) 2987.2,2366.94 cw(c2976.59,2356.33) 2987.2,2345.73 2940.61,2299.13 ccw(c2951.21,2288.53) 2940.61,2277.92 ccw(c2951.21,2288.53) 2961.82,2277.92 2963.23,2279.33 cw(c2973.84,2268.73) 2984.45,2279.33 3003.79,2259.99 3003.79,2240.13 3572.01,1671.9 3591.88,1671.9 v1(3594.49,1669.29)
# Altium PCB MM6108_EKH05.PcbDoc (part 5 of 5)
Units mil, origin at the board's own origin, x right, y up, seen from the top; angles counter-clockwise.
Board outline 6023.62 x 3425.2 mil, 4 copper layers (Top Layer, Ground Plane, Middle Layer, Bottom Layer), stack 76.15 mil thick; 212 components, 163 nets, 749 pads, 1477 vias.

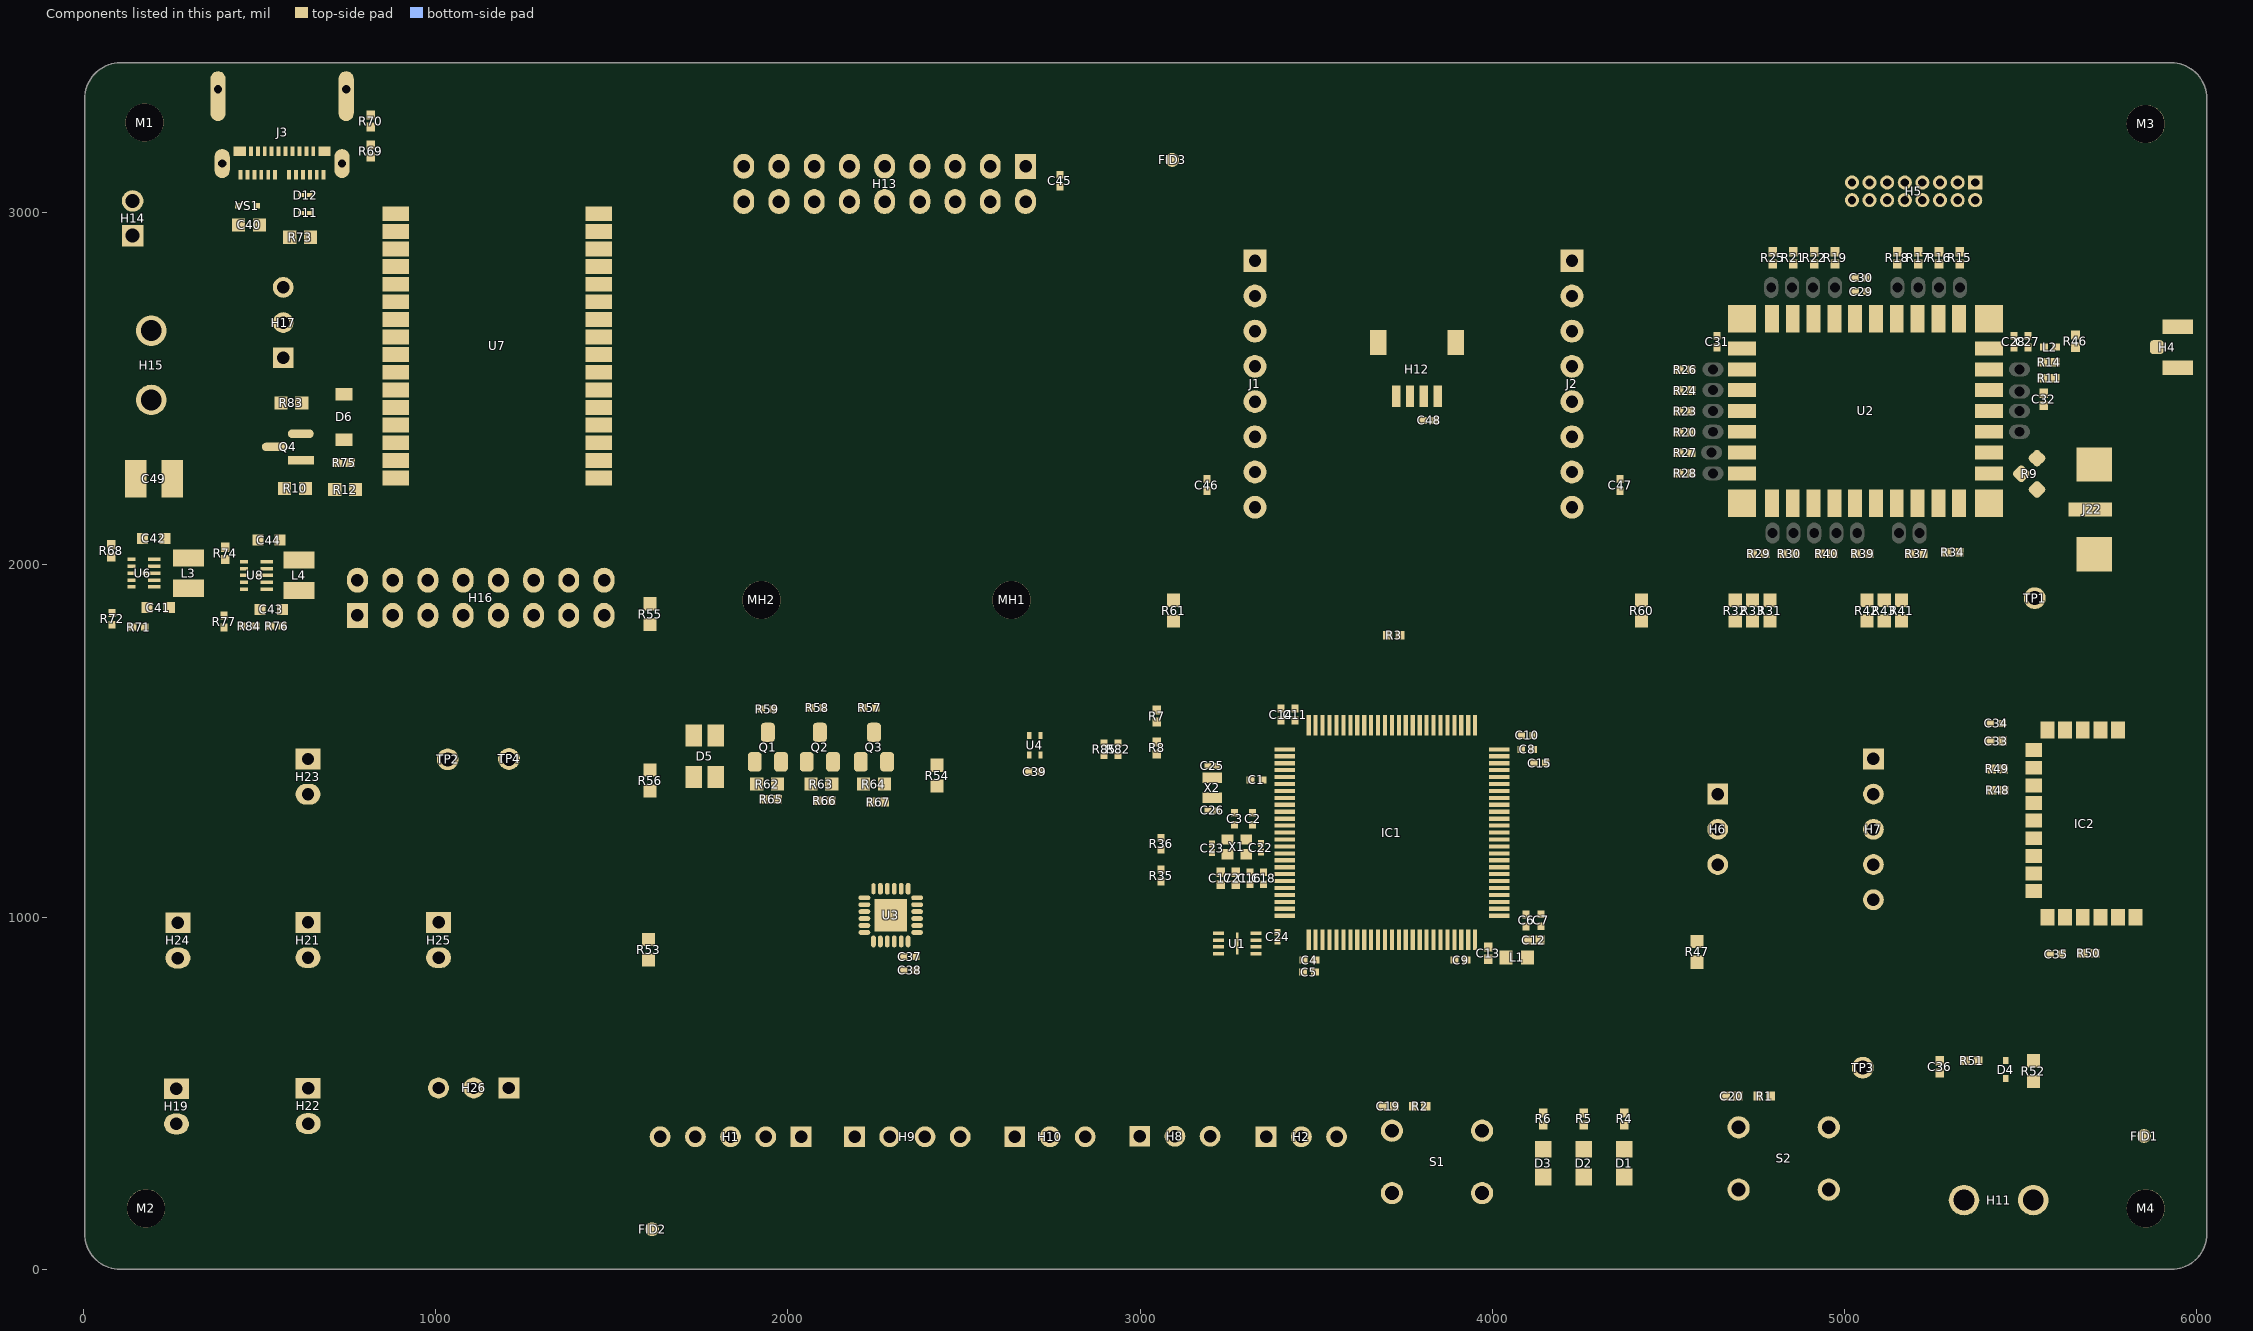
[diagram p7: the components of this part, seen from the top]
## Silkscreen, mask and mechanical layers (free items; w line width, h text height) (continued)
Fab Notes:
  drawing of 11 lines, arcs and shapes, not listed
  text "NOTES: UNLESS OTHERWISE SPECIFIED0" at -3357.21,2832.86 h60
  text "1. SPECIFICATIONS/TOLERANCES:" at -3357.21,2762.86 h60
  text "A. FABRICATE PER IPC-6012, CLASS 2, USING PROVIDED DATA FILES XXXXXXXX.ZIP" at -3357.21,2692.86 h60
  text "B. ALL SPECIFICATIONS USED SHALL BE PER THEIR LATEST REVISIONS." at -3357.21,2622.86 h60
  text "C. THE DIMENSIONS OF CIRCUIT FEATURES IN THE PROVIDED DATA MAY BE ADJUSTED" at -3357.21,2552.86 h60
  text "ONLY TO COMPENSATE FOR PROCESS TOLERANCES; ADDING, REMOVING OR RELOCATING" at -3357.21,2482.86 h60
  text "CIRCUIT FEATURES IS NOT ALLOWED" at -3357.21,2412.86 h60
  text "D. REMOVE ALL BURRS AND BREAK SHARP EDGES, .381 [.015] MAX RADIUS." at -3357.21,2342.86 h60
  text "E. PARENTHETICAL INFORMATION IS FOR REFERENCE ONLY." at -3357.21,2272.86 h60
  text "F. REPAIR OF PCB DEFECTS IS NOT PERMITTED." at -3357.21,2202.86 h60
  text "2. DIELECTRIC MATERIAL:" at -3357.25,2062.86 h60
  text "A. DIELECTRIC MATERIAL SHALL BE PER IPC-4101/99, /124, /126 OR /129 (RoHS COMPLIANT EPOXY-GLASS)" at -3357.21,1992.86 h60
  text "B. MINIMUM DIELECTRIC THICKNESS SHALL BE .051 [.002] FOR REFERENCED STACK-UP" at -3357.21,1922.86 h60
  text "DIMENSIONS OF.076 [.003] OR GREATER; IPC-6012 REQUIREMENTS SHALL OTHERWISE" at -3357.21,1852.86 h60
  text "APPLY. SINGLE-PLY CONSTRUCTION IS ALLOWED." at -3357.21,1782.86 h60
  text "C. SEE LAYER STACK-UP FOR REQUIRED COPPER WEIGHTS AND THE FINISHED PCB" at -3357.21,1712.86 h60
  text "THICKNESS. IF SPECIFIED, 1/3 OZ. STARTING FOIL MAY BE ACHIEVED BY 1/2 OZ. FOIL REDUCTION." at -3357.21,1642.86 h60
  text "D. FINISHED PCB THICKNESS SHALL BE MEASURED OVER LANDS AND/OR" at -3357.21,1572.86 h60
  text "CONDUCTORS NOT COVERED BY SOLDER MASK. IF SPECIFIED, 1/3 OZ. STARTING FOIL" at -3357.21,1502.86 h60
  text "MAY BE ACHIEVED BY 1/2 OZ. FOIL REDUCTION." at -3357.21,1432.86 h60
  text "3. DRILLING:" at -3357.21,1292.86 h60
  text "A. VIA DIAMETERS SHALL BE VERIFIED BEFORE PLATING; ALL OTHER HOLE" at -3357.21,1222.86 h60
  text "DIAMETERS ARE FINISHED DIMENSIONS." at -3357.21,1152.86 h60
  text "B. LAYER-TO-LAYER MISREGISTRATION SHALL BE .127 [.005] MAXIMUM." at -3357.21,1082.86 h60
  text "4. SOLDER MASK:" at -3357.21,942.86 h60
  text "A. APPLY LPI SOLDER MASK OVER BARE COPPER USING PROVIDED DATA." at -3357.21,872.86 h60
  text "B. SOLDER MASK SHALL BE PER IPC-SM-840, CLASS T, COLOR PURPLE." at -3357.21,802.86 h60
  text "C. THE DIMENSIONS OF SOLDER MASK-DEFINED PADS ON PLANES AND/OR WIDE" at -3357.21,732.86 h60
  text "CONDUCTORS SHALL NOT BE MODIFIED." at -3357.21,662.86 h60
  text "5. SILKSCREEN/MARKING:" at -3357.21,522.86 h60
  text "A. SILKSCREEN PCB PER PROVIDED DATA USING PERMANENT, NON-CONDUCTIVE" at -3357.21,452.86 h60
  text "INK, COLOR WHITE." at -3357.21,382.86 h60
  text "B. SUPPLIER ID AND TRACEABILITY INFORMATION SHALL NOT / BE APPLIED ON ANY PART OF THE PCB" at -3356.19,209.11 h60
  text "C. INK SHALL NOT BE APPLIED TO ANY SOLDERABLE SURFACE." at -3357.21,133.49 h60
  text "USING PROVIDED DATA." at -3357.21,63.49 h60
  text "6. ELECTRICAL TEST:" at -3357.21,-76.51 h60
  text "A. DESIGN VERIFICATION SHALL BE DONE PRIOR TO PCB FABRICATION USING" at -3357.21,-146.51 h60
  text "GERBER DATA AND AN IPC-D-356 NETLIST." at -3357.21,-216.51 h60
  text "B. ALL PCBS SHALL BE 100% ELECTRICALLY TESTED FOR OPENS AND SHORTS" at -3357.21,-286.51 h60
  text "C. APPLY TEST STAMP IN NON-LEGEND AREA ON SECONDARY SIDE OF PCB." at -3357.21,-356.51 h60
  text "7. FINAL FINISH:" at -3357.21,-491.51 h60
  text "A. FINAL FINISH SHALL BE ELECTROLESS NICKEL/IMMERSION GOLD (ENIG) PER IPC-4552." at -3357.21,-565.54 h60
  text "Project:" at 492.34,-665.41 h60
  text "EKH05" at 753.17,-670.33 h80
  text "8. IMPEDANCE:" at -3360.68,-673.63 h60
  text "A. IMPEDANCE TOLERANCE SHALL BE +/- 10%." at -3360.68,-743.63 h60
  text "Company:" at 492.34,-755.96 h60
  text "Morse Micro" at 753.22,-760.88 h80
  text "B. SEE LAYER STACK-UP FOR IMPEDANCE REQUIREMENTS." at -3360.68,-813.63 h60
  text "Drawn By:" at 492.34,-846.51 h60
  text ".DrawnBy" at 753.17,-853.4 h80
  text "9. IF PANELIZATION SPECIFICATIONS ARE PROVIDED, THE PCBS SHALL BE DELIVERED IN PANEL" at -3347.21,-936.51 h60
  text "FORM. HOWEVER, THESE SPECIFICATIONS MAY BE REPLACED BY SUPPLIER PREFERRED" at -3347.21,-1006.51 h60
  text "Date:" at 492.34,-1027.06 h60
  text "Rev:" at 1210.84,-1031 h60
  text ".Print_Date" at 753.17,-1037.89 h80
  text ".Rev" at 1338.8,-1038.76 h80
  text "(SPECIFICATIONS AS APPROVED)." at -3347.21,-1076.51 h60
Board:
  drawing of 167 lines, arcs and shapes, not listed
